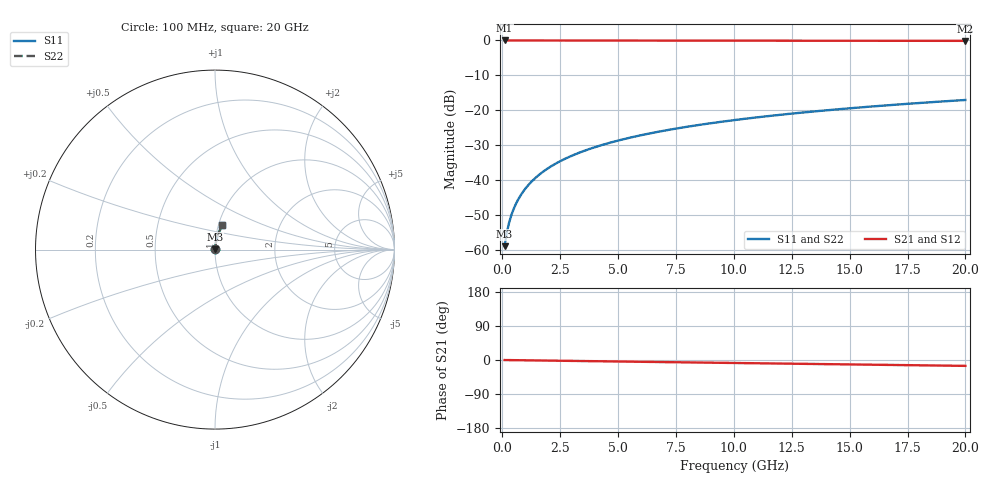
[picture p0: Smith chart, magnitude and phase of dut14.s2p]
! Touchstone file exported from HFSS 2026.1.0
!  File:  C:/ffzhzh/LocalFiles/Ansys_Project_Files/temp_test_TMRDL_14_1782907073_13352.aedt
!  Generated:  07:59:02 PM Jul  1, 2026
!  Design:  TMRDL
!  Project:  temp_test_TMRDL_14_1782907073_13352
! Variables:
!  h_bsmrdl = 2um
!  h_ox = 20um
!  h_rdl = 5um
!  h_sub = 80um
!  h_tmrdl = 4.24um
!  h_tsv = 80um
!  h_via = 3um
!  l_bsmrdl = 300um
!  l_sub = 595.98um
!  l_tmrdl = 195.98um
!  m_sub = 200um
!  pitch = 52.9um
!  r_tsv = 6um
!  s_tmrdl = 10um
!  w_bsmrdl = 18um
!  w_sub = 500um
!  w_tmrdl = 28.21um
!  x_tsv_center1 = 210.085um
!  x_tsv_center2 = 528.085um
!  x_tsv_center3 = 752.275um
!  x_tsv_center4 = 1070.275um
!  x_tsv_center5 = 1294.465um
!  x_tsv_center6 = 1612.465um
# GHz S MA R 50.000000
! Terminal data exported
! Port[1] = TM_RDL1_1_T1
! Port[2] = TM_RDL1_1_T2
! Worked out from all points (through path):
!   200 points, 100 MHz to 20 GHz, reference 50 ohm
!   highest |S21| = -0.01 dB at 100 MHz (marker M1); lowest = -0.1 dB at 20 GHz (marker M2)
!   group delay of S21, straight-line fit = 2.15 ps
!   lowest |S11| = -58.8 dB at 100 MHz (marker M3), VSWR 1.00, Z = 50.1 + j0.0837 ohm
!   |S11| at or under -10 dB: start of sweep to end of sweep
!   |S22| runs from -58.8 to -17.0 dB; largest |S21 - S12| = 2.6e-15
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0.1  0.001152 46.5  0.9992 -0.1  0.9992 -0.1  0.001152 46.5
! Gamma 0 0 0 0
! Port Impedance 50 0 50 0
0.2  0.001834 62.1  0.9991 -0.2  0.9991 -0.2  0.001834 62.1
0.3  0.002544 69.0  0.9991 -0.2  0.9991 -0.2  0.002544 69.0
0.4  0.003261 73.0  0.9991 -0.3  0.9991 -0.3  0.003261 73.0
0.5  0.003984 75.7  0.999 -0.4  0.999 -0.4  0.003984 75.7
0.6  0.004714 77.6  0.999 -0.5  0.999 -0.5  0.004714 77.6
0.8  0.006186 80.0  0.999 -0.6  0.999 -0.6  0.006186 80.0
1.1  0.008413 82.0  0.9989 -0.9  0.9989 -0.9  0.008413 82.0
1.5  0.01139 83.3  0.9988 -1.2  0.9988 -1.2  0.01139 83.3
1.8  0.01363 83.7  0.9988 -1.4  0.9988 -1.4  0.01363 83.7
2.1  0.01587 84.0  0.9987 -1.7  0.9987 -1.7  0.01587 84.0
2.7  0.02032 84.1  0.9985 -2.2  0.9985 -2.2  0.02032 84.1
3.5  0.02621 83.9  0.9981 -2.8  0.9981 -2.8  0.02621 83.9
4.2  0.03133 83.6  0.9978 -3.3  0.9978 -3.3  0.03133 83.6
5  0.03714 83.1  0.9974 -4.0  0.9974 -4.0  0.03714 83.1
5.9  0.04362 82.6  0.997 -4.7  0.997 -4.7  0.04362 82.6
6.8  0.05006 82.0  0.9965 -5.4  0.9965 -5.4  0.05006 82.0
8.3  0.06072 81.0  0.9956 -6.5  0.9956 -6.5  0.06072 81.0
10.1  0.0734 79.8  0.9944 -7.9  0.9944 -7.9  0.0734 79.8
13.4  0.09636 77.5  0.992 -10.5  0.992 -10.5  0.09636 77.5
16.7  0.1189 75.2  0.9891 -13.0  0.9891 -13.0  0.1189 75.2
20  0.1411 72.8  0.9859 -15.5  0.9859 -15.5  0.1411 72.8
